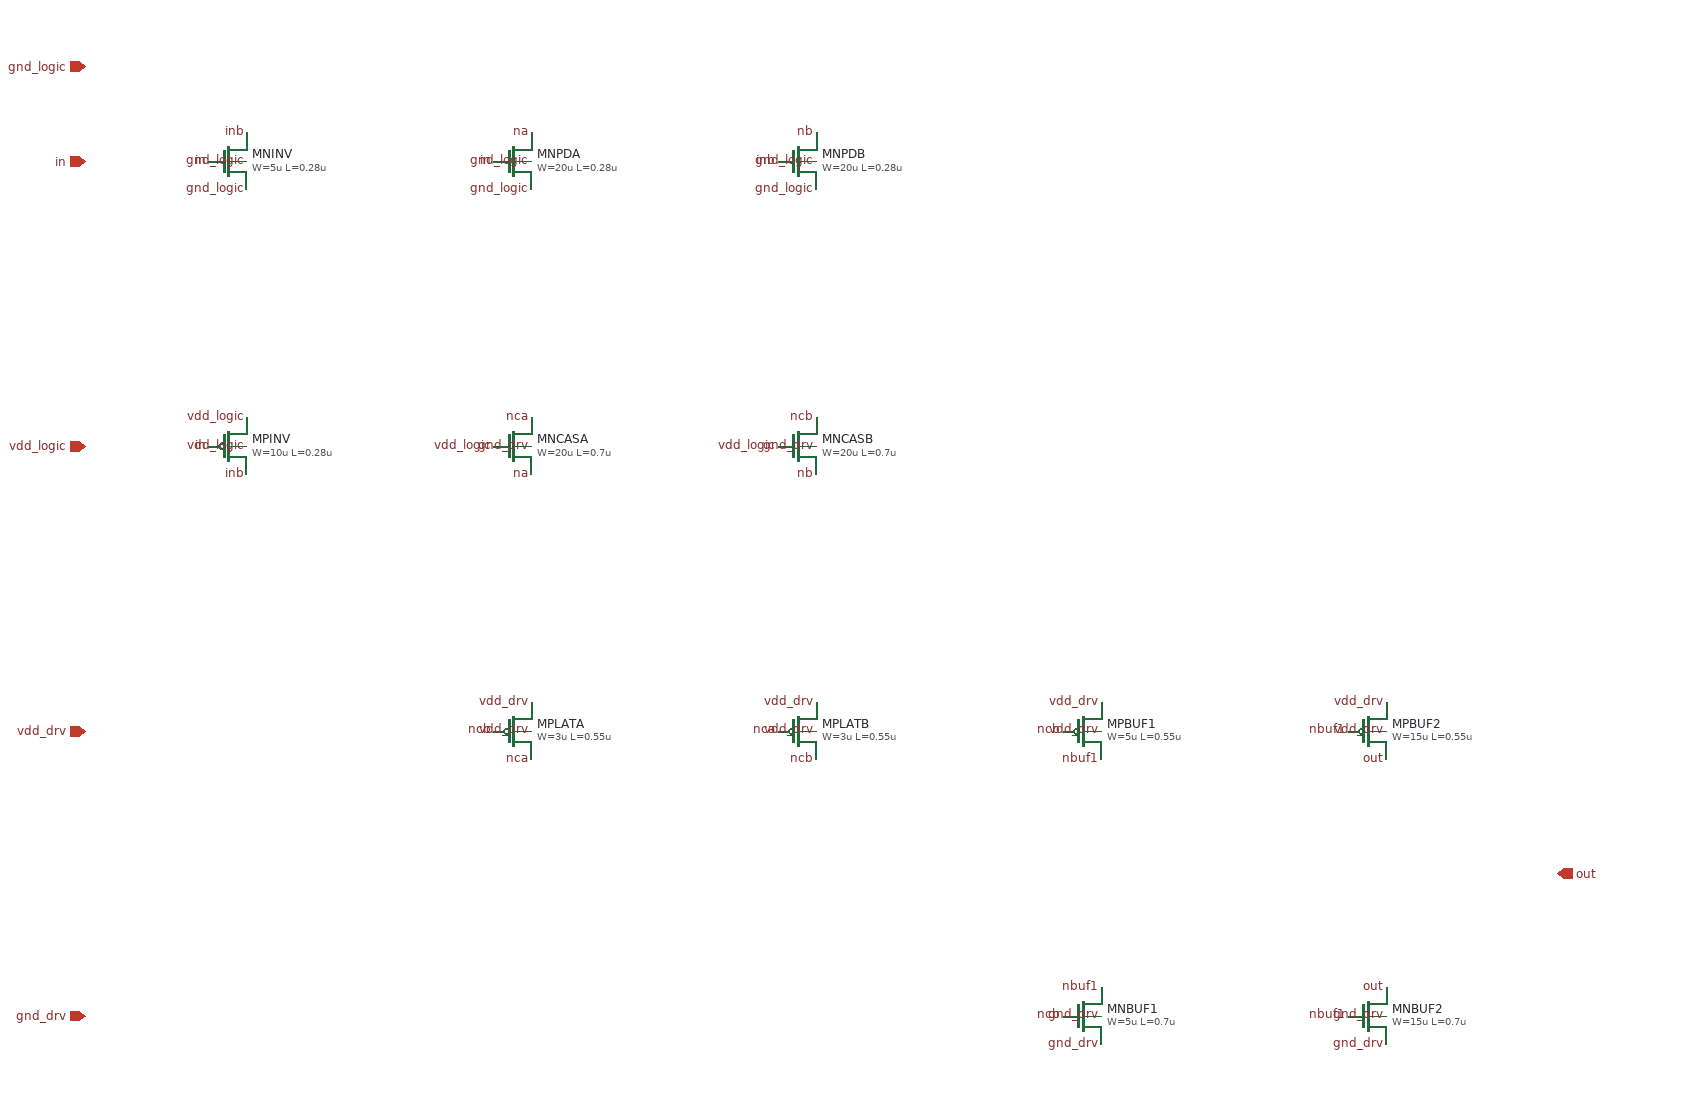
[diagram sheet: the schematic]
v {xschem version=3.4.7 file_version=1.2
* level_shifter -- cascode/clamped 3.3V-logic to 5V/6V-drive-rail level shifter
* spec/gate-driver.md sec4; see design/level-shifter-partition.md for the domain
* partition and cascode-bias derivation. Generated by hand per xschem text format,
* net connectivity verified via `xschem -x -n -s` (see PR description).
}
G {}
K {}
V {}
S {}
E {}
C {symbols/nfet_03v3.sym} 0 0 0 0 {name=MNINV
L=0.28u
W=5u
model=nfet_03v3
spiceprefix=X}
C {devices/lab_pin.sym} 20 -30 0 0 {name=l1 sig_type=std_logic lab=inb}
C {devices/lab_pin.sym} -20 0 0 0 {name=l2 sig_type=std_logic lab=in}
C {devices/lab_pin.sym} 20 30 0 0 {name=l3 sig_type=std_logic lab=gnd_logic}
C {devices/lab_pin.sym} 20 0 0 0 {name=l4 sig_type=std_logic lab=gnd_logic}
C {symbols/pfet_03v3.sym} 0 300 0 0 {name=MPINV
L=0.28u
W=10u
model=pfet_03v3
spiceprefix=X}
C {devices/lab_pin.sym} 20 330 0 0 {name=l5 sig_type=std_logic lab=inb}
C {devices/lab_pin.sym} -20 300 0 0 {name=l6 sig_type=std_logic lab=in}
C {devices/lab_pin.sym} 20 270 0 0 {name=l7 sig_type=std_logic lab=vdd_logic}
C {devices/lab_pin.sym} 20 300 0 0 {name=l8 sig_type=std_logic lab=vdd_logic}
C {symbols/nfet_03v3.sym} 300 0 0 0 {name=MNPDA
L=0.28u
W=20u
model=nfet_03v3
spiceprefix=X}
C {devices/lab_pin.sym} 320 -30 0 0 {name=l9 sig_type=std_logic lab=na}
C {devices/lab_pin.sym} 280 0 0 0 {name=l10 sig_type=std_logic lab=in}
C {devices/lab_pin.sym} 320 30 0 0 {name=l11 sig_type=std_logic lab=gnd_logic}
C {devices/lab_pin.sym} 320 0 0 0 {name=l12 sig_type=std_logic lab=gnd_logic}
C {symbols/nfet_03v3.sym} 600 0 0 0 {name=MNPDB
L=0.28u
W=20u
model=nfet_03v3
spiceprefix=X}
C {devices/lab_pin.sym} 620 -30 0 0 {name=l13 sig_type=std_logic lab=nb}
C {devices/lab_pin.sym} 580 0 0 0 {name=l14 sig_type=std_logic lab=inb}
C {devices/lab_pin.sym} 620 30 0 0 {name=l15 sig_type=std_logic lab=gnd_logic}
C {devices/lab_pin.sym} 620 0 0 0 {name=l16 sig_type=std_logic lab=gnd_logic}
C {symbols/nfet_06v0.sym} 300 300 0 0 {name=MNCASA
L=0.7u
W=20u
model=nfet_06v0
spiceprefix=X}
C {devices/lab_pin.sym} 320 270 0 0 {name=l17 sig_type=std_logic lab=nca}
C {devices/lab_pin.sym} 280 300 0 0 {name=l18 sig_type=std_logic lab=vdd_logic}
C {devices/lab_pin.sym} 320 330 0 0 {name=l19 sig_type=std_logic lab=na}
C {devices/lab_pin.sym} 320 300 0 0 {name=l20 sig_type=std_logic lab=gnd_drv}
C {symbols/nfet_06v0.sym} 600 300 0 0 {name=MNCASB
L=0.7u
W=20u
model=nfet_06v0
spiceprefix=X}
C {devices/lab_pin.sym} 620 270 0 0 {name=l21 sig_type=std_logic lab=ncb}
C {devices/lab_pin.sym} 580 300 0 0 {name=l22 sig_type=std_logic lab=vdd_logic}
C {devices/lab_pin.sym} 620 330 0 0 {name=l23 sig_type=std_logic lab=nb}
C {devices/lab_pin.sym} 620 300 0 0 {name=l24 sig_type=std_logic lab=gnd_drv}
C {symbols/pfet_06v0.sym} 300 600 0 0 {name=MPLATA
L=0.55u
W=3u
model=pfet_06v0
spiceprefix=X}
C {devices/lab_pin.sym} 320 630 0 0 {name=l25 sig_type=std_logic lab=nca}
C {devices/lab_pin.sym} 280 600 0 0 {name=l26 sig_type=std_logic lab=ncb}
C {devices/lab_pin.sym} 320 570 0 0 {name=l27 sig_type=std_logic lab=vdd_drv}
C {devices/lab_pin.sym} 320 600 0 0 {name=l28 sig_type=std_logic lab=vdd_drv}
C {symbols/pfet_06v0.sym} 600 600 0 0 {name=MPLATB
L=0.55u
W=3u
model=pfet_06v0
spiceprefix=X}
C {devices/lab_pin.sym} 620 630 0 0 {name=l29 sig_type=std_logic lab=ncb}
C {devices/lab_pin.sym} 580 600 0 0 {name=l30 sig_type=std_logic lab=nca}
C {devices/lab_pin.sym} 620 570 0 0 {name=l31 sig_type=std_logic lab=vdd_drv}
C {devices/lab_pin.sym} 620 600 0 0 {name=l32 sig_type=std_logic lab=vdd_drv}
C {symbols/pfet_06v0.sym} 900 600 0 0 {name=MPBUF1
L=0.55u
W=5u
model=pfet_06v0
spiceprefix=X}
C {devices/lab_pin.sym} 920 630 0 0 {name=l33 sig_type=std_logic lab=nbuf1}
C {devices/lab_pin.sym} 880 600 0 0 {name=l34 sig_type=std_logic lab=ncb}
C {devices/lab_pin.sym} 920 570 0 0 {name=l35 sig_type=std_logic lab=vdd_drv}
C {devices/lab_pin.sym} 920 600 0 0 {name=l36 sig_type=std_logic lab=vdd_drv}
C {symbols/nfet_06v0.sym} 900 900 0 0 {name=MNBUF1
L=0.7u
W=5u
model=nfet_06v0
spiceprefix=X}
C {devices/lab_pin.sym} 920 870 0 0 {name=l37 sig_type=std_logic lab=nbuf1}
C {devices/lab_pin.sym} 880 900 0 0 {name=l38 sig_type=std_logic lab=ncb}
C {devices/lab_pin.sym} 920 930 0 0 {name=l39 sig_type=std_logic lab=gnd_drv}
C {devices/lab_pin.sym} 920 900 0 0 {name=l40 sig_type=std_logic lab=gnd_drv}
C {symbols/pfet_06v0.sym} 1200 600 0 0 {name=MPBUF2
L=0.55u
W=15u
model=pfet_06v0
spiceprefix=X}
C {devices/lab_pin.sym} 1220 630 0 0 {name=l41 sig_type=std_logic lab=out}
C {devices/lab_pin.sym} 1180 600 0 0 {name=l42 sig_type=std_logic lab=nbuf1}
C {devices/lab_pin.sym} 1220 570 0 0 {name=l43 sig_type=std_logic lab=vdd_drv}
C {devices/lab_pin.sym} 1220 600 0 0 {name=l44 sig_type=std_logic lab=vdd_drv}
C {symbols/nfet_06v0.sym} 1200 900 0 0 {name=MNBUF2
L=0.7u
W=15u
model=nfet_06v0
spiceprefix=X}
C {devices/lab_pin.sym} 1220 870 0 0 {name=l45 sig_type=std_logic lab=out}
C {devices/lab_pin.sym} 1180 900 0 0 {name=l46 sig_type=std_logic lab=nbuf1}
C {devices/lab_pin.sym} 1220 930 0 0 {name=l47 sig_type=std_logic lab=gnd_drv}
C {devices/lab_pin.sym} 1220 900 0 0 {name=l48 sig_type=std_logic lab=gnd_drv}
C {devices/ipin.sym} -150 0 0 0 {name=p_in lab=in}
C {devices/ipin.sym} -150 300 0 0 {name=p_vddl lab=vdd_logic}
C {devices/ipin.sym} -150 -100 0 0 {name=p_gndl lab=gnd_logic}
C {devices/ipin.sym} -150 600 0 0 {name=p_vddd lab=vdd_drv}
C {devices/ipin.sym} -150 900 0 0 {name=p_gndd lab=gnd_drv}
C {devices/opin.sym} 1400 750 0 0 {name=p_out lab=out}
